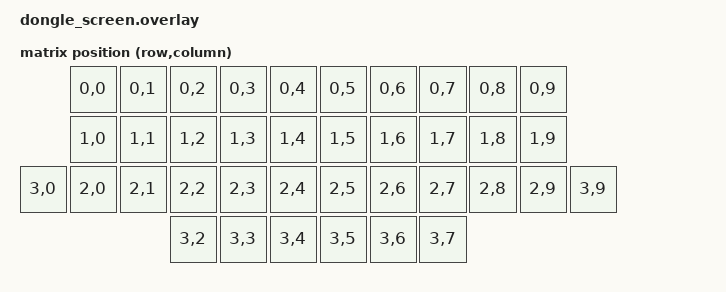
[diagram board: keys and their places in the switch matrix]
#include <dt-bindings/zmk/matrix_transform.h>

/ {
    chosen {
        zephyr,display = &st7789;
     
        zmk,backlight = &disp_bl;
    };

    /* PWM 백라이트 정의 */
    pwmleds {
        compatible = "pwm-leds";
        disp_bl: pwm_led_1 {
            pwms = <&pwm1 0 PWM_MSEC(1) PWM_POLARITY_NORMAL>;
        };
    };

    default_transform: keymap_transform_0 {
        compatible = "zmk,matrix-transform";
        columns = <10>;
        rows = <4>;
        map = <
                RC(0,0) RC(0,1) RC(0,2) RC(0,3) RC(0,4)    RC(0,5) RC(0,6) RC(0,7) RC(0,8) RC(0,9)
                RC(1,0) RC(1,1) RC(1,2) RC(1,3) RC(1,4)    RC(1,5) RC(1,6) RC(1,7) RC(1,8) RC(1,9)
        RC(3,0) RC(2,0) RC(2,1) RC(2,2) RC(2,3) RC(2,4)    RC(2,5) RC(2,6) RC(2,7) RC(2,8) RC(2,9) RC(3,9)
                                RC(3,2) RC(3,3) RC(3,4)    RC(3,5) RC(3,6) RC(3,7)
        >;
    };
};

/* 핀 컨트롤 설정 (SPI3 및 PWM1) */
&pinctrl {
    spi3_default: spi3_default {
        group1 {
            psels = <NRF_PSEL(SPIM_SCK, 1, 13)>,
                    <NRF_PSEL(SPIM_MOSI, 1, 15)>,
                    <NRF_PSEL(SPIM_MISO, 1, 10)>;
        };
    };

    spi3_sleep: spi3_sleep {
        group1 {
            psels = <NRF_PSEL(SPIM_SCK, 1, 13)>,
                    <NRF_PSEL(SPIM_MOSI, 1, 15)>,
                    <NRF_PSEL(SPIM_MISO, 1, 10)>;
            low-power-enable;
        };
